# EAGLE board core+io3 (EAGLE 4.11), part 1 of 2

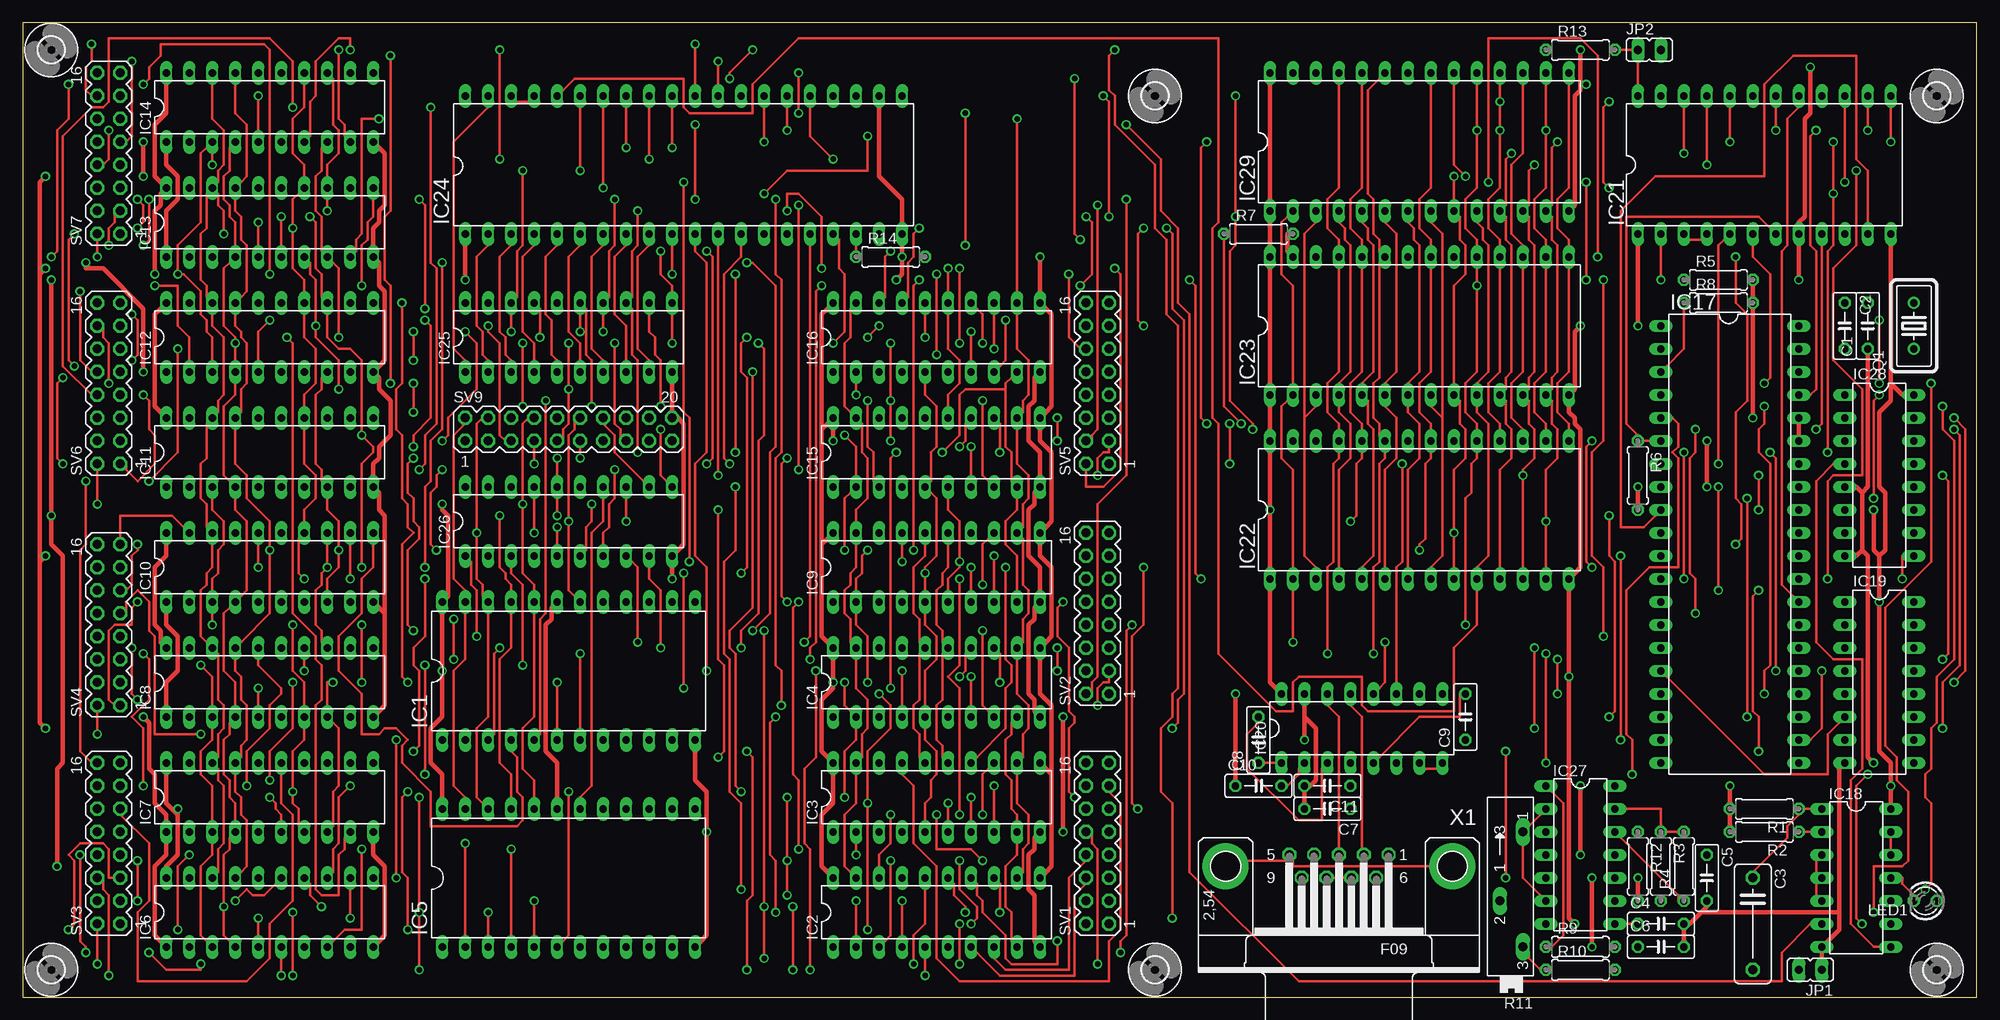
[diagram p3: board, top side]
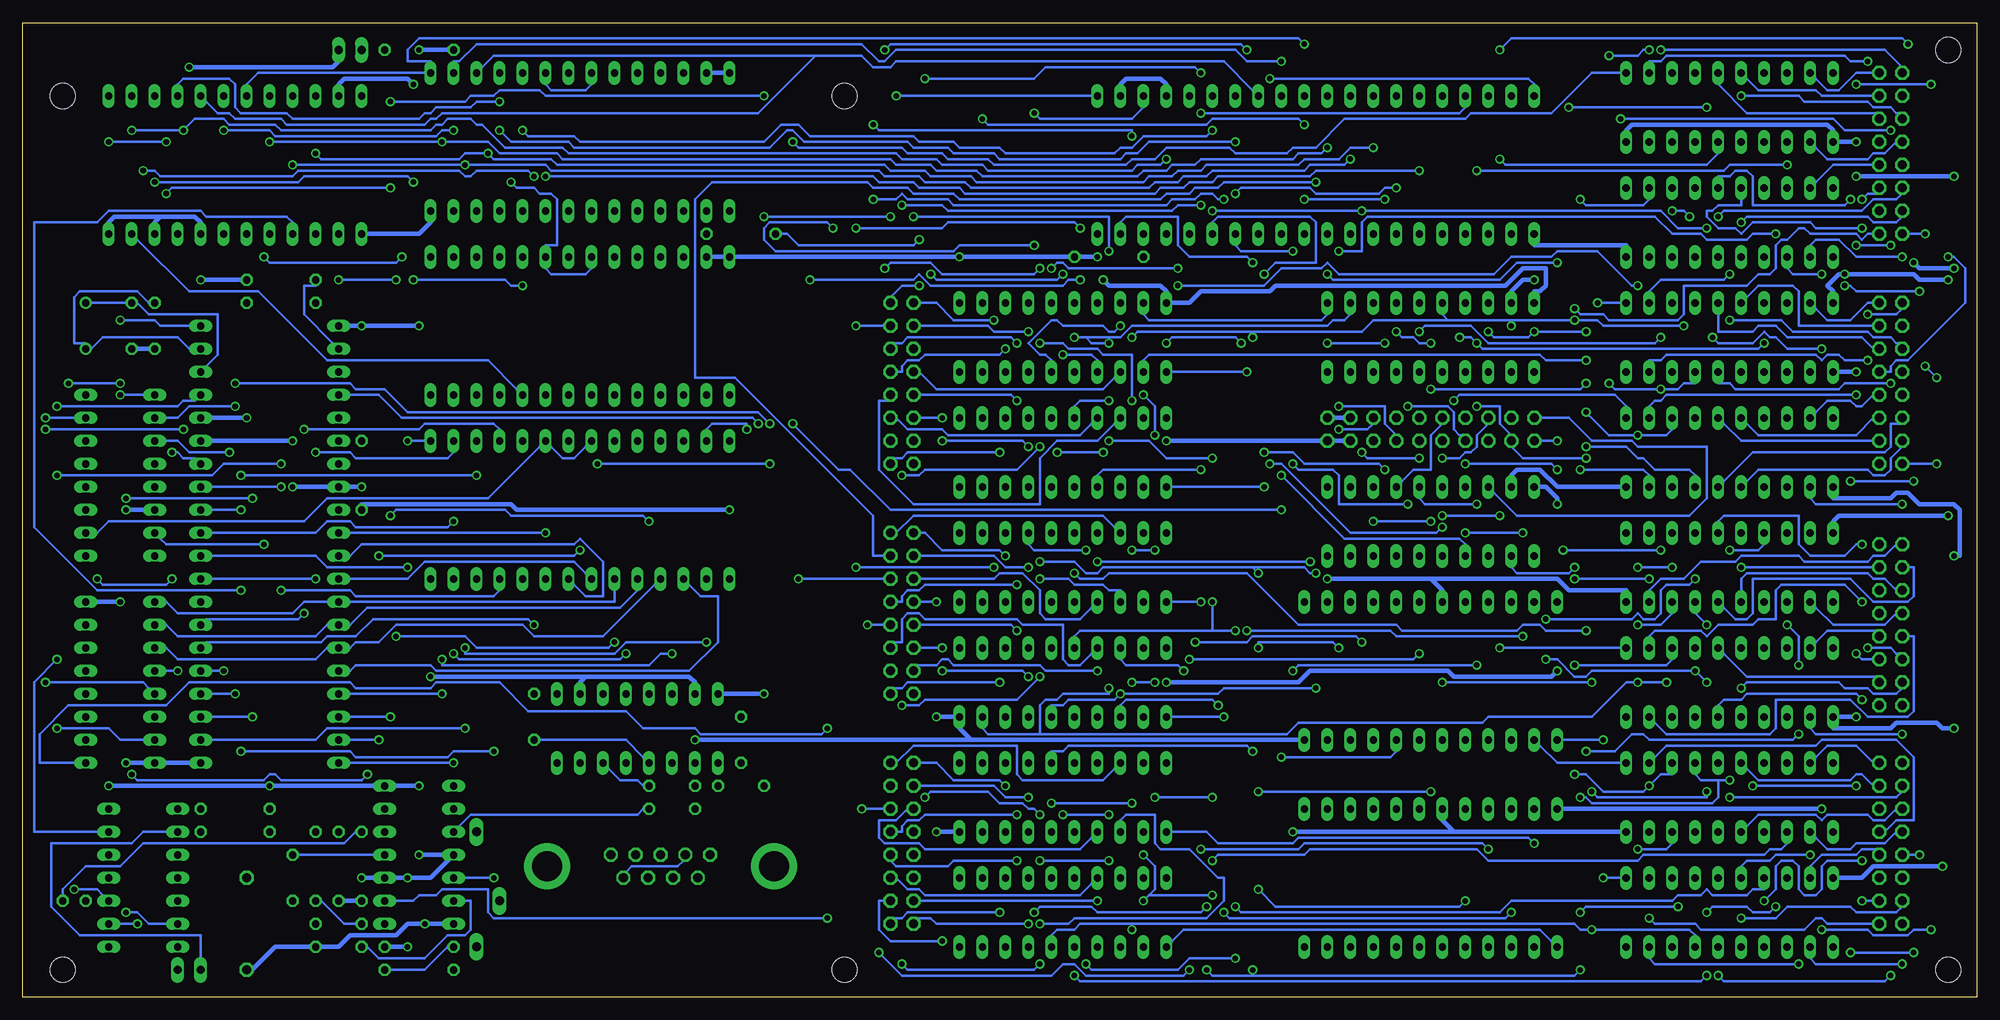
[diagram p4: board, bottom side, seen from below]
Size 215.88 x 107.62 mm. Coordinates in mm from the lower left corner, seen from the top.
Outline: 0,0 215.88,0 215.88,107.62 0,107.62 0,0
Copper layers (1*16): Top 0.035mm / dielectric 1.5mm / Bottom 0.035mm
Design rules "default": minimum track width 10mil, minimum drill 24mil, track to track 8mil, track to pad 8mil, pad to pad 8mil, via to via 8mil, smd to smd 8mil, copper to edge 40mil, drill to drill 8mil, minimum pad ring 10mil, minimum via ring 8mil, stop-mask expansion 4mil, vias tented up to drill 0mil, thermal gap 10mil
Net classes: 1 Power: width 0.508 mm, drill 0.254 mm, clearance 0.254 mm

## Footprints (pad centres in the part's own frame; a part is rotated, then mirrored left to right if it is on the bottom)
C050-025X075 = drill 0.813 octagon: 1 -2.54,0; 2 2.54,0
C102-043X133 = drill 1.016 octagon: 1 -5.08,0; 2 5.08,0
DIL24-6 = drill 0.813 long: 1 -13.97,-7.62; 2 -11.43,-7.62; 3 -8.89,-7.62; 4 -6.35,-7.62; 5 -3.81,-7.62; 6 -1.27,-7.62; 7 1.27,-7.62; 8 3.81,-7.62; 9 6.35,-7.62; 10 8.89,-7.62; 11 11.43,-7.62; 12 13.97,-7.62; 13 13.97,7.62; 14 11.43,7.62; 15 8.89,7.62; 16 6.35,7.62; 17 3.81,7.62; 18 1.27,7.62; 19 -1.27,7.62; 20 -3.81,7.62; 21 -6.35,7.62; 22 -8.89,7.62; 23 -11.43,7.62; 24 -13.97,7.62
DIL20 = drill 0.813 long: 1 -11.43,-3.81; 2 -8.89,-3.81; 3 -6.35,-3.81; 4 -3.81,-3.81; 5 -1.27,-3.81; 6 1.27,-3.81; 7 3.81,-3.81; 8 6.35,-3.81; 9 8.89,-3.81; 10 11.43,-3.81; 11 11.43,3.81; 12 8.89,3.81; 13 6.35,3.81; 14 3.81,3.81; 15 1.27,3.81; 16 -1.27,3.81; 17 -3.81,3.81; 18 -6.35,3.81; 19 -8.89,3.81; 20 -11.43,3.81
DIL40 = drill 0.813 long: 1 -24.13,-7.62; 2 -21.59,-7.62; 3 -19.05,-7.62; 4 -16.51,-7.62; 5 -13.97,-7.62; 6 -11.43,-7.62; 7 -8.89,-7.62; 8 -6.35,-7.62; 9 -3.81,-7.62; 10 -1.27,-7.62; 11 1.27,-7.62; 12 3.81,-7.62; 13 6.35,-7.62; 14 8.89,-7.62; 15 11.43,-7.62; 16 13.97,-7.62; 17 16.51,-7.62; 18 19.05,-7.62; 19 21.59,-7.62; 20 24.13,-7.62; 21 24.13,7.62; 22 21.59,7.62; 23 19.05,7.62; 24 16.51,7.62; 25 13.97,7.62; 26 11.43,7.62; 27 8.89,7.62; 28 6.35,7.62; 29 3.81,7.62; 30 1.27,7.62; 31 -1.27,7.62; 32 -3.81,7.62; 33 -6.35,7.62; 34 -8.89,7.62; 35 -11.43,7.62; 36 -13.97,7.62; 37 -16.51,7.62; 38 -19.05,7.62; 39 -21.59,7.62; 40 -24.13,7.62
DIL14 = drill 0.813 long: 1 -7.62,-3.81; 2 -5.08,-3.81; 3 -2.54,-3.81; 4 0,-3.81; 5 2.54,-3.81; 6 5.08,-3.81; 7 7.62,-3.81; 8 7.62,3.81; 9 5.08,3.81; 10 2.54,3.81; 11 0,3.81; 12 -2.54,3.81; 13 -5.08,3.81; 14 -7.62,3.81
DIL16 = drill 0.813 long: 1 -8.89,-3.81; 2 -6.35,-3.81; 3 -3.81,-3.81; 4 -1.27,-3.81; 5 1.27,-3.81; 6 3.81,-3.81; 7 6.35,-3.81; 8 8.89,-3.81; 9 8.89,3.81; 10 6.35,3.81; 11 3.81,3.81; 12 1.27,3.81; 13 -1.27,3.81; 14 -3.81,3.81; 15 -6.35,3.81; 16 -8.89,3.81
DIL24 = drill 0.813 long: 1 -13.97,-7.62; 2 -11.43,-7.62; 3 -8.89,-7.62; 4 -6.35,-7.62; 5 -3.81,-7.62; 6 -1.27,-7.62; 7 1.27,-7.62; 8 3.81,-7.62; 9 6.35,-7.62; 10 8.89,-7.62; 11 11.43,-7.62; 12 13.97,-7.62; 13 13.97,7.62; 14 11.43,7.62; 15 8.89,7.62; 16 6.35,7.62; 17 3.81,7.62; 18 1.27,7.62; 19 -1.27,7.62; 20 -3.81,7.62; 21 -6.35,7.62; 22 -8.89,7.62; 23 -11.43,7.62; 24 -13.97,7.62
DIL28 = drill 0.813 long: 1 -16.51,-7.62; 2 -13.97,-7.62; 3 -11.43,-7.62; 4 -8.89,-7.62; 5 -6.35,-7.62; 6 -3.81,-7.62; 7 -1.27,-7.62; 8 1.27,-7.62; 9 3.81,-7.62; 10 6.35,-7.62; 11 8.89,-7.62; 12 11.43,-7.62; 13 13.97,-7.62; 14 16.51,-7.62; 15 16.51,7.62; 16 13.97,7.62; 17 11.43,7.62; 18 8.89,7.62; 19 6.35,7.62; 20 3.81,7.62; 21 1.27,7.62; 22 -1.27,7.62; 23 -3.81,7.62; 24 -6.35,7.62; 25 -8.89,7.62; 26 -11.43,7.62; 27 -13.97,7.62; 28 -16.51,7.62
JP1 = drill 0.914 long: 1 0,-1.27; 2 0,1.27
LED3MM = drill 0.813 octagon: A -1.27,0; K 1.27,0
HC18U-V = drill 0.813 round: 1 -2.54,0; 2 2.54,0
0207/7 = drill 0.813 octagon: 1 -3.81,0; 2 3.81,0
SP19L = drill 1.016 long: A 5.715,-1.27; E -6.985,-1.27; S -1.905,1.27
MA08-2 = drill 1.016 octagon: 1 -8.89,-1.27; 2 -8.89,1.27; 3 -6.35,-1.27; 4 -6.35,1.27; 5 -3.81,-1.27; 6 -3.81,1.27; 7 -1.27,-1.27; 8 -1.27,1.27; 9 1.27,-1.27; 10 1.27,1.27; 11 3.81,-1.27; 12 3.81,1.27; 13 6.35,-1.27; 14 6.35,1.27; 15 8.89,-1.27; 16 8.89,1.27
MA10-2 = drill 1.016 octagon: 1 -11.43,-1.27; 2 -11.43,1.27; 3 -8.89,-1.27; 4 -8.89,1.27; 5 -6.35,-1.27; 6 -6.35,1.27; 7 -3.81,-1.27; 8 -3.81,1.27; 9 -1.27,-1.27; 10 -1.27,1.27; 11 1.27,-1.27; 12 1.27,1.27; 13 3.81,-1.27; 14 3.81,1.27; 15 6.35,-1.27; 16 6.35,1.27; 17 8.89,-1.27; 18 8.89,1.27; 19 11.43,-1.27; 20 11.43,1.27
2,8 = hole 2.8: 0,0
F09HP = drill 1.016 octagon: 1 -5.486,-1.27; 2 -2.743,-1.27; 3 0,-1.27; 4 2.743,-1.27; 5 5.486,-1.27; 6 -4.115,1.27; 7 -1.372,1.27; 8 1.372,1.27; 9 4.115,1.27 | drill 3.302 pad 5.08 round: G1 -12.522,0; G2 12.522,0

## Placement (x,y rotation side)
C1  27pf  [C050-025X075]  203.83,74.13 90 top
C2  27pf  [C050-025X075]  201.29,74.13 270 top
C3  22uf  [C102-043X133]  191.13,8.09 270 top
C4  0.1uf  [C050-025X075]  180.97,8.09 0 top
C5  10uf  [C050-025X075]  186.05,13.17 270 top
C6  330pf  [C050-025X075]  180.97,5.55 0 top
C7  10uf  [C050-025X075]  144.14,20.79 180 top
C8  0.1uf  [C050-025X075]  136.52,28.41 90 top
C9  0.1uf  [C050-025X075]  159.38,30.95 90 top
C10  0.1uf  [C050-025X075]  136.52,23.33 0 top
C11  0.1uf  [C050-025X075]  144.14,23.33 180 top
IC1  74154N  [DIL24-6]  60.32,36.03 0 top
IC2  74LS373N  [DIL20]  100.96,9.36 0 top
IC3  74LS373N  [DIL20]  100.96,22.06 0 top
IC4  74LS373N  [DIL20]  100.96,34.76 0 top
IC5  74154N  [DIL24-6]  60.32,13.17 0 top
IC6  74LS374N  [DIL20]  27.3,9.36 0 top
IC7  74LS374N  [DIL20]  27.3,22.06 0 top
IC8  74LS374N  [DIL20]  27.3,34.76 0 top
IC9  74LS373N  [DIL20]  100.96,47.46 0 top
IC10  74LS374N  [DIL20]  27.3,47.46 0 top
IC11  74LS374N  [DIL20]  27.3,60.16 0 top
IC12  74LS374N  [DIL20]  27.3,72.86 0 top
IC13  74LS374N  [DIL20]  27.3,85.56 0 top
IC14  74LS374N  [DIL20]  27.3,98.26 0 top
IC15  74LS373N  [DIL20]  100.96,60.16 0 top
IC16  74LS373N  [DIL20]  100.96,72.86 0 top
IC17  [DIL40]  188.59,50 270 top
IC18  74LS00N  [DIL14]  202.56,13.17 270 top
IC19  74LS138N  [DIL16]  205.1,34.76 270 top
IC20  MAX232  [DIL16]  147.95,29.68 0 top
IC21  [DIL24]  192.4,91.91 0 top
IC22  5565  [DIL28]  154.3,53.81 0 top
IC23  2764  [DIL28]  154.3,74.13 0 top
IC24  [DIL40]  73.02,91.91 0 top
IC25  74LS245N  [DIL20]  60.32,72.86 0 top
IC26  74LS245N  [DIL20]  60.32,52.54 0 top
IC27  LM556N  [DIL14]  172.08,15.71 270 top
IC28  74LS138N  [DIL16]  205.1,57.62 270 top
IC29  2764  [DIL28]  154.3,94.45 0 top
JP1  RESET  [JP1]  197.48,3.01 90 top
JP2  DEBUG  [JP1]  179.7,104.61 270 top
LED1  [LED3MM]  210.18,10.63 180 top
Q1  4Mhz  [HC18U-V]  208.91,74.13 90 top
R1  10K  [0207/7]  192.4,20.79 180 top
R2  10K  [0207/7]  192.4,18.25 180 top
R3  100K  [0207/7]  180.97,14.44 270 top
R4  100K  [0207/7]  183.51,14.44 90 top
R5  3.3K  [0207/7]  187.32,79.21 0 top
R6  3.3K  [0207/7]  178.43,57.62 270 top
R7  3.3K  [0207/7]  136.52,84.29 0 top
R8  3.3K  [0207/7]  187.32,76.67 0 top
R9  1.8K  [0207/7]  172.08,5.55 0 top
R10  10K  [0207/7]  172.08,3.01 0 top
R11  10K  [SP19L]  164.46,12.54 90 top
R12  270  [0207/7]  178.43,14.44 270 top
R13  1K  [0207/7]  172.08,104.61 0 top
R14  3.3K  [0207/7]  95.88,81.75 0 top
SV1  [MA08-2]  118.74,16.98 90 top
SV2  [MA08-2]  118.74,42.38 90 top
SV3  [MA08-2]  9.52,16.98 90 top
SV4  [MA08-2]  9.52,41.11 90 top
SV5  [MA08-2]  118.74,67.78 90 top
SV6  [MA08-2]  9.52,67.78 90 top
SV7  [MA08-2]  9.52,93.18 90 top
SV9  [MA10-2]  60.32,62.7 0 top
U$1  [2,8]  125.09,3.01 0 top
U$2  [2,8]  125.09,99.53 0 top
U$3  [2,8]  3.17,104.61 0 top
U$4  [2,8]  3.17,3.01 0 top
U$5  [2,8]  211.45,99.53 0 top
U$6  [2,8]  211.45,3.01 0 top
X1  [F09HP]  145.41,14.44 180 top

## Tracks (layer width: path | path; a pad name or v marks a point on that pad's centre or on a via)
A00
  Top 0.254: IC17.9 180.34,53.17 179.06,51.91 176.53,51.91 176.53,86.83 180.34,90.64 192.4,90.64 192.4,100.8 195.57,103.97 202.56,103.97 202.56,92.55 203.83,91.28 203.83,85.56 IC21.11 | IC29.10 160.65,85.56 161.28,84.92 161.28,83.66 161.92,83.02 161.92,69.05 160.65,67.78 IC23.10 160.65,65.24 160.65,64.61 161.92,63.34 161.92,48.73 160.65,47.46 IC22.10 160.65,44.92 160.65,41.11 158.11,38.57 158.11,31.58 148.59,31.58 147.95,32.22 147.95,35.39 140.97,35.39 140.33,34.76 140.33,31.58 138.42,31.58 132.07,37.94 132.07,63.34 131.44,63.97 131.44,84.92 132.07,85.56 132.07,105.88 85.72,105.88 80.64,100.8 80.64,97.62 73.66,97.62 73.02,98.26 73.02,101.44 60.96,101.44 59.69,100.16 IC24.36
  Bottom 0.254: IC21.11 203.19,83.66 197.48,77.94 189.86,77.94 182.24,70.32 164.46,70.32 161.28,67.14 IC23.10
A01  (via drill 0.61)
  Top 0.254: IC22.9 158.11,47.46 v158.11,51.27 158.11,58.25 159.38,59.52 159.38,62.7 158.75,63.34 158.75,65.88 IC23.9 158.11,67.78 158.11,78.58 159.38,79.84 159.38,83.02 158.75,83.66 158.75,86.19 IC29.9 158.11,88.1 v158.11,90.64 | v61.59,91.28 61.59,98.26 IC24.35
  Bottom 0.254: v61.59,91.28 73.02,91.28 73.66,90.64 83.81,90.64 84.45,90 86.99,90 87.62,89.37 90.16,89.37 90.8,88.73 111.75,88.73 112.39,89.37 116.83,89.37 117.47,90 121.28,90 121.91,90.64 v158.11,90.64 | v158.11,51.27 179.7,51.27 IC17.10
A02
  Top 0.254: 156.84,63.97 156.84,48.73 155.57,47.46 IC22.8 | 156.84,63.97 155.57,65.24 IC23.8 | 156.84,63.97 156.84,84.29 155.57,85.56 IC29.8
  Bottom 0.254: IC17.11 179.7,48.73 178.43,50 154.94,50 154.3,50.63 151.76,48.09 151.76,44.28 153.66,44.28 154.94,45.55 IC22.8
A03
  Top 0.254: IC22.7 153.03,47.46 153.03,58.25 154.3,59.52 154.3,63.34 153.03,64.61 153.03,65.24 IC23.7 153.03,67.78 154.3,69.05 154.3,83.02 153.66,83.66 153.66,84.92 153.03,85.56 IC29.7
  Bottom 0.254: IC17.12 179.7,46.19 173.35,46.19 171.44,48.09 154.94,48.09 153.66,46.82 IC22.7
A04
  Top 0.254: IC29.6 150.49,85.56 151.76,84.29 151.76,69.05 150.49,67.78 IC23.6 150.49,65.24 151.76,63.97 151.76,59.52 150.49,58.25 150.49,47.46 IC22.6
  Bottom 0.254: IC22.6 150.49,44.92 150.49,43.65 179.7,43.65 IC17.13 182.24,43.65 184.78,43.65 186.05,42.38 198.75,42.38 200.02,43.65 IC19.1
A05
  Top 0.254: IC22.5 147.95,47.46 149.22,48.73 149.22,62.7 148.59,63.34 148.59,65.88 IC23.5 147.95,67.78 149.22,69.05 149.22,83.02 148.59,83.66 148.59,84.92 147.95,85.56 IC29.5
  Bottom 0.254: IC19.2 200.02,41.11 198.75,39.84 183.51,39.84 182.24,41.11 IC17.14 179.7,41.11 177.79,43.02 149.85,43.02 147.95,44.92 IC22.5
A06
  Top 0.254: IC22.4 145.41,47.46 145.41,58.25 146.68,59.52 146.68,63.34 145.41,64.61 145.41,65.24 IC23.4 145.41,67.78 146.68,69.05 146.68,83.02 146.04,83.66 146.04,84.92 145.41,85.56 IC29.4
  Bottom 0.254: IC19.3 200.02,38.57 198.75,37.3 183.51,37.3 182.24,38.57 IC17.15 179.7,38.57 179.06,39.2 176.53,39.2 174.62,41.11 160.65,41.11 159.38,39.84 151.76,39.84 146.04,45.55 IC22.4
A07
  Top 0.254: IC17.16 181.6,35.39 192.4,24.6 199.38,24.6 199.38,29.04 200.66,30.31 IC19.6 | 141.6,63.97 141.6,48.73 142.87,47.46 IC22.3 | 141.6,63.97 142.87,65.24 IC23.3 | 141.6,63.97 141.6,84.29 142.87,85.56 IC29.3
  Bottom 0.254: IC17.16 179.7,36.03 179.06,36.66 170.81,36.66 170.17,36.03 142.23,36.03 139.06,39.2 139.06,44.28 140.97,44.28 142.23,45.55 IC22.3
A08  (via drill 0.61)
  Top 0.254: IC29.25 145.41,100.8 145.41,89.37 144.14,88.1 144.14,84.92 145.41,83.66 145.41,83.02 IC23.25 145.41,80.48 145.41,69.05 144.14,67.78 144.14,64.61 145.41,63.34 145.41,62.7 IC22.25 145.41,60.16 145.41,59.52 144.78,58.89 144.78,48.09 144.14,47.46 v144.14,37.94 | v169.54,37.3 v169.54,33.49
  Bottom 0.254: v169.54,33.49 179.7,33.49 IC17.17 | v169.54,37.3 169.54,36.66 146.68,36.66 145.41,37.94 v144.14,37.94
A09  (via drill 0.61)
  Top 0.254: IC29.24 147.95,100.8 147.95,89.37 146.68,88.1 146.68,84.92 147.95,83.66 147.95,83.02 IC23.24 147.95,80.48 147.95,69.05 146.68,67.78 146.68,64.61 147.95,63.34 147.95,62.7 IC22.24 147.95,60.16 147.95,59.52 147.31,58.89 147.31,53.17 v146.68,52.54 | v175.25,30.95 175.89,31.58 175.89,48.09 175.25,48.73 v175.25,53.17
  Bottom 0.254: v175.25,30.95 179.7,30.95 IC17.18 | v175.25,53.17 174.62,53.81 162.56,53.81 161.92,53.17 147.31,53.17 v146.68,52.54
A10  (via drill 0.61)
  Top 0.254: IC29.21 155.57,100.8 155.57,89.37 154.3,88.1 154.3,84.92 155.57,83.66 155.57,83.02 IC23.21 155.57,80.48 155.57,69.05 154.3,67.78 154.3,64.61 155.57,63.34 155.57,62.7 IC22.21 155.57,60.16 155.57,59.52 154.94,58.89 154.94,50.63 154.3,50 v154.3,49.37 | v176.53,48.73 v176.53,28.41
  Bottom 0.254: v176.53,28.41 179.7,28.41 IC17.19 | v176.53,48.73 154.94,48.73 v154.3,49.37
A11  (via drill 0.61)
  Top 0.254: IC29.23 149.85,101.44 148.59,100.16 148.59,88.73 149.22,88.1 149.22,84.29 149.85,83.66 149.85,82.39 IC23.23 149.85,81.11 149.85,68.41 149.22,67.78 149.22,63.97 149.85,63.34 149.85,62.06 IC22.23 150.49,60.16 150.49,59.52 149.85,58.89 149.85,48.09 149.22,47.46 v149.22,37.94 | v168.27,37.94 v168.27,25.87
  Bottom 0.254: v168.27,25.87 179.7,25.87 IC17.20 | v168.27,37.94 167.63,37.3 149.85,37.3 v149.22,37.94
A12  (via drill 0.61)
  Top 0.254: v198.75,36.03 198.75,29.68 197.48,28.41 IC17.22 | IC29.2 139.69,86.19 139.06,85.56 139.06,79.84 140.33,78.58 140.33,67.78 IC23.2 139.69,65.88 139.06,65.24 139.06,59.52 140.33,58.25 140.33,47.46 IC22.2 140.33,44.92 v140.33,39.2 | v167,38.57 v167,29.68
  Bottom 0.254: v198.75,36.03 200.02,36.03 IC19.4 | v167,29.68 182.24,29.68 183.51,28.41 194.94,28.41 IC17.22 | v167,38.57 167,37.94 150.49,37.94 149.22,39.2 v140.33,39.2
A13  (via drill 0.61)
  Top 0.254: v190.5,55.08 v190.5,30.95 | v204.47,55.08 204.47,65.88 v205.1,66.51
  Bottom 0.254: v190.5,30.95 194.94,30.95 IC17.23 | v204.47,55.08 v190.5,55.08 | v205.1,66.51 202.56,66.51 IC28.1
A14  (via drill 0.61)
  Top 0.254: v192.4,33.49 192.4,36.03 193.03,36.66 193.03,58.89 191.76,60.16 191.76,62.7 192.4,63.34 v192.4,65.24
  Bottom 0.254: v192.4,33.49 194.94,33.49 IC17.24 | v192.4,65.24 197.48,65.24 198.75,63.97 200.02,63.97 IC28.2
A15  (via drill 0.61)
  Top 0.254: v193.67,36.03 193.67,59.52 v193.03,60.16
  Bottom 0.254: v193.67,36.03 194.94,36.03 IC17.25 | v193.03,60.16 197.48,60.16 198.75,61.43 200.02,61.43 IC28.3
AB\
  Bottom 0.254: IC22.22 153.66,60.8 154.94,59.52 156.2,59.52 157.47,60.8 IC22.20 158.75,60.8 164.46,55.08 182.24,55.08 184.78,52.54 206.37,52.54 207.64,51.27 IC28.10
CB1
  Top 0.254: R14.1 92.07,82.39 92.07,83.02 IC24.18
CD\  (via drill 0.61)
  Top 0.254: v207.64,46.19 207.64,48.73 IC28.9 | v199.38,46.19 199.38,56.98 200.02,57.62 203.19,57.62 203.19,67.14 200.02,70.32 200.02,80.48 202.56,83.02 v202.56,91.28 | v159.38,90.64 158.11,91.91 158.11,100.8 IC29.20
  Bottom 0.254: IC29.20 158.11,100.8 157.47,100.16 153.66,100.16 153.03,100.8 IC29.22 | v207.64,46.19 207,45.55 200.02,45.55 v199.38,46.19 | v202.56,91.28 201.29,91.28 200.66,90.64 186.05,90.64 185.41,91.28 167.63,91.28 167,90.64 166.37,90.64 165.73,91.28 160.01,91.28 v159.38,90.64
D0  (via drill 0.61)
  Top 0.254: IC22.11 163.19,47.46 163.19,58.25 164.46,59.52 164.46,62.7 163.82,63.34 163.82,65.88 IC23.11 163.82,67.14 163.82,68.41 164.46,69.05 164.46,83.02 163.82,83.66 163.82,86.19 IC29.11 163.82,87.47 163.82,92.55 v164.46,93.18 | v66.67,93.81 66.67,98.26 IC24.33 | v183.51,93.18 183.51,98.26 IC21.22 | v187.32,44.92 v187.32,56.35
  Bottom 0.254: v66.67,93.81 69.21,93.81 70.48,92.55 74.29,92.55 74.92,91.91 85.08,91.91 85.72,91.28 88.26,91.28 88.89,90.64 91.44,90.64 92.07,90 110.48,90 111.12,90.64 115.56,90.64 116.2,91.28 120.01,91.28 120.64,91.91 156.84,91.91 157.47,92.55 163.82,92.55 v164.46,93.18 167,93.18 167.63,92.55 182.88,92.55 v183.51,93.18 | v187.32,56.35 194.94,56.35 IC17.33 | v187.32,44.92 179.7,44.92 179.06,44.28 163.82,44.28 163.19,44.92 IC22.11
D1  (via drill 0.61)
  Top 0.254: IC22.12 165.73,47.46 v165.73,57.62 165.73,58.25 167,59.52 167,62.7 166.37,63.34 166.37,65.88 IC23.12 166.37,67.14 166.37,68.41 167,69.05 167,83.02 166.37,83.66 166.37,86.19 IC29.12 166.37,87.47 166.37,91.28 v167,91.91 | v69.21,92.55 69.21,98.26 IC24.32 | v186.05,91.91 186.05,98.26 IC21.21 | v191.76,57.62 v191.76,53.81
  Bottom 0.254: v69.21,92.55 69.84,91.91 73.66,91.91 74.29,91.28 84.45,91.28 85.08,90.64 87.62,90.64 88.26,90 90.8,90 91.44,89.37 111.12,89.37 111.75,90 116.2,90 116.83,90.64 120.64,90.64 121.28,91.28 157.47,91.28 158.11,91.91 v167,91.91 v186.05,91.91 | v191.76,53.81 194.94,53.81 IC17.32 | v165.73,57.62 v191.76,57.62
D2  (via drill 0.61)
  Top 0.254: IC22.13 168.27,47.46 v168.27,52.54 168.27,58.25 169.54,59.52 169.54,62.7 168.91,63.34 168.91,65.88 IC23.13 168.91,67.14 168.91,68.41 169.54,69.05 169.54,83.02 168.91,83.66 168.91,86.19 IC29.13 168.91,87.47 168.91,93.81 v169.54,94.45 | v71.75,93.81 71.75,98.26 IC24.31 | v188.59,94.45 188.59,98.26 IC21.20
  Bottom 0.254: v71.75,93.81 72.38,93.18 74.92,93.18 75.56,92.55 85.72,92.55 86.35,91.91 88.89,91.91 89.53,91.28 92.07,91.28 92.7,90.64 109.85,90.64 110.48,91.28 114.93,91.28 115.56,91.91 119.38,91.91 120.01,92.55 156.2,92.55 156.84,93.18 163.19,93.18 164.46,94.45 v169.54,94.45 v188.59,94.45 | v168.27,52.54 168.91,51.91 179.06,51.91 179.7,52.54 182.24,52.54 183.51,51.27 194.94,51.27 IC17.31
D3  (via drill 0.61)
  Top 0.254: IC22.15 170.81,62.7 170.81,63.34 169.54,64.61 169.54,67.78 170.81,69.05 170.81,80.48 IC23.15 170.81,83.02 170.81,83.66 169.54,84.92 169.54,88.1 170.81,89.37 170.81,100.8 IC29.15 | v74.29,105.25 74.29,100.8 IC24.30 | v173.35,47.46 172.72,48.09 172.72,60.8 v173.35,61.43
  Bottom 0.254: v74.29,105.25 74.92,105.88 172.08,105.88 173.35,104.61 173.35,103.34 170.81,103.34 IC29.15 171.44,102.07 189.86,102.07 191.13,100.8 IC21.19 | v173.35,47.46 182.24,47.46 183.51,48.73 194.94,48.73 IC17.30 | v173.35,61.43 171.44,61.43 IC22.15
D4  (via drill 0.61)
  Top 0.254: IC22.16 168.27,62.7 168.27,63.34 167,64.61 167,67.78 168.27,69.05 168.27,80.48 IC23.16 168.27,83.02 168.27,83.66 167,84.92 167,88.1 168.27,89.37 v168.27,95.72 168.27,100.8 IC29.16 | v76.83,103.34 76.83,100.8 IC24.29 | v193.67,95.72 193.67,98.26 IC21.18 | v183.51,60.16 v183.51,46.19
  Bottom 0.254: v76.83,103.34 80.64,103.34 81.91,104.61 119.38,104.61 120.64,103.34 121.28,103.34 123.19,105.25 165.73,105.25 167.63,103.34 168.27,103.34 IC29.16 | v193.67,95.72 188.59,95.72 187.95,95.08 170.17,95.08 169.54,95.72 v168.27,95.72 | v183.51,46.19 194.94,46.19 IC17.29 | v183.51,60.16 179.7,60.16 179.06,59.52 168.91,59.52 168.27,60.16 IC22.16
D5
  Top 0.254: IC17.28 195.57,44.28 194.31,45.55 194.31,82.39 194.94,83.02 194.94,96.99 196.21,98.26 IC21.17 | IC22.17 165.73,62.7 164.46,63.97 164.46,67.78 165.73,69.05 165.73,80.48 IC23.17 165.73,83.02 164.46,84.29 164.46,91.91 165.73,93.18 165.73,100.8 IC29.17
  Bottom 0.254: 128.27,103.97 163.82,103.97 165.09,102.7 IC29.17 | 128.27,103.97 123.19,103.97 121.91,102.7 120.01,102.7 119.38,103.34 83.18,103.34 80,100.16 IC24.28 | 128.27,103.97 134.62,97.62 169.54,97.62 170.17,96.99 170.81,96.99 171.44,96.36 186.69,96.36 187.32,96.99 192.4,96.99 193.03,97.62 194.31,97.62 195.57,98.89 IC21.17
D6  (via drill 0.61)
  Top 0.254: IC22.18 163.19,62.7 163.19,63.34 161.92,64.61 161.92,67.78 163.19,69.05 163.19,80.48 IC23.18 163.19,83.02 163.19,83.66 161.92,84.92 161.92,88.1 163.19,89.37 v163.19,95.72 v163.19,98.89 163.19,100.8 IC29.18 | v81.91,94.45 81.91,98.26 IC24.27 | v184.78,42.38 184.78,46.19 184.14,46.82 184.14,59.52 184.78,60.16 v184.78,62.7
  Bottom 0.254: v81.91,94.45 91.44,94.45 92.7,93.18 93.97,93.18 94.61,92.55 107.94,92.55 108.58,93.18 113.02,93.18 113.66,93.81 117.47,93.81 118.1,94.45 129.53,94.45 130.81,95.72 131.44,95.72 133.34,93.81 154.94,93.81 155.57,94.45 161.92,94.45 v163.19,95.72 | v184.78,42.38 185.41,41.74 195.57,41.74 IC17.27 | v184.78,62.7 172.08,62.7 171.44,63.34 163.82,63.34 163.19,62.7 IC22.18 | v163.19,98.89 165.73,98.89 166.37,98.26 170.17,98.26 170.81,97.62 171.44,97.62 172.08,96.99 186.05,96.99 186.69,97.62 191.76,97.62 192.4,98.26 192.4,100.8 193.03,101.44 198.12,101.44 198.75,100.8 IC21.16
D7  (via drill 0.61)
  Top 0.254: IC29.19 160.65,100.8 v160.65,95.72 160.65,89.37 159.38,88.1 159.38,84.92 160.65,83.66 160.65,83.02 IC23.19 160.65,80.48 v160.65,78.58 160.65,69.05 159.38,67.78 159.38,64.61 160.65,63.34 160.65,62.7 IC22.19 160.65,60.16 160.65,59.52 160.01,58.89 160.01,55.71 159.38,55.08 v159.38,41.11 | v84.45,95.72 84.45,98.26 IC24.26 | v201.29,90 201.29,98.26 IC21.15 | v172.72,79.21 v172.72,90
  Bottom 0.254: v84.45,95.72 85.08,95.08 92.07,95.08 93.34,93.81 94.61,93.81 95.24,93.18 107.31,93.18 107.94,93.81 112.39,93.81 113.02,94.45 116.83,94.45 117.47,95.08 128.9,95.08 130.17,96.36 132.07,96.36 133.98,94.45 154.3,94.45 154.94,95.08 160.01,95.08 v160.65,95.72 | v159.38,41.11 160.01,41.74 177.16,41.74 179.06,39.84 182.24,39.84 182.88,39.2 195.57,39.2 IC17.26 | v201.29,90 185.41,90 184.78,90.64 173.35,90.64 v172.72,90 | v172.72,79.21 162.56,79.21 161.92,78.58 v160.65,78.58
E  (via drill 0.61)
  Top 0.254: v198.12,95.72 197.48,95.08 197.48,83.02 198.12,82.39 198.12,67.14 197.48,66.51 IC17.37 | v203.83,95.72 203.83,98.26 IC21.14 | v89.53,92.55 86.99,95.08 86.99,98.26 IC24.25 | v210.18,11.9 210.81,12.54 210.81,21.42 210.18,22.06 210.18,24.6 210.81,25.23 210.81,29.68 211.45,30.31 211.45,35.39 213.35,37.3 213.35,61.43 212.09,62.7 v212.09,65.24
  Bottom 0.254: v203.83,95.72 v198.12,95.72 196.84,96.99 193.67,96.99 193.03,96.36 187.95,96.36 187.32,95.72 170.81,95.72 170.17,96.36 169.54,96.36 168.91,96.99 166.37,96.99 165.73,96.36 165.09,96.36 162.56,93.81 156.2,93.81 155.57,93.18 119.38,93.18 118.74,92.55 114.93,92.55 114.3,91.91 109.85,91.91 109.21,91.28 93.34,91.28 92.7,91.91 90.16,91.91 v89.53,92.55 | v210.18,11.9 207.64,11.9 207,11.27 IC18.10 | v212.09,65.24 198.75,65.24 198.12,65.88 196.84,65.88 IC17.37
EF\  (via drill 0.61)
  Top 0.254: v189.22,50 189.86,50.63 189.86,54.45 189.22,55.08 189.22,64.61 190.5,65.88 190.5,75.4 189.22,76.67 v189.22,81.75 | v173.98,81.75 173.98,103.97 172.08,105.88 161.92,105.88 v161.92,90
  Bottom 0.254: IC23.22 153.03,80.48 153.66,79.84 157.47,79.84 158.11,80.48 IC23.20 158.11,83.02 156.84,83.02 156.84,88.1 157.47,88.73 158.75,88.73 159.38,89.37 161.28,89.37 v161.92,90 | v189.22,50 200.02,50 200.66,50.63 IC28.7 | v189.22,81.75 188.59,81.11 174.62,81.11 v173.98,81.75
GND  (via drill 0.61)
  Top 0.508: 203.19,49.37 202.56,48.73 IC28.8 | 203.19,49.37 203.19,55.71 | 203.19,55.71 203.83,56.35 203.83,70.95 C1.1 | 203.19,55.71 202.56,56.35 IC28.5 | C6.2 183.51,6.18 183.51,7.46 C4.2 184.14,8.09 185.41,9.36 | 203.19,49.37 203.83,48.73 203.83,26.5 v204.47,25.87 | C7.2 141.6,21.42 141.6,22.7 C11.2 142.23,23.33 142.87,23.96 142.87,29.68 141.6,30.95 | 141.6,30.95 141.6,32.22 IC20.15 | v178.43,74.13 178.43,83.02 IC21.1 | 172.08,100.8 172.08,100.16 171.44,99.53 171.44,87.47 IC29.14 | 172.08,100.8 v172.08,104.61 | 172.08,100.8 v172.72,100.8 | v172.08,74.13 171.44,73.5 171.44,67.14 IC23.14 170.81,65.24 170.81,64.61 171.44,63.97 171.44,63.34 172.08,62.7 172.08,47.46 171.44,46.82 IC22.14 170.81,44.92 v170.81,35.39 170.81,8.73 v171.44,8.09 | IC13.1 15.87,83.02 15.87,86.83 17.14,88.1 17.14,90.64 15.87,91.91 15.87,93.18 IC14.1 | IC6.1 15.24,6.18 14.6,6.82 14.6,14.44 15.87,15.71 15.87,16.98 IC7.1 15.87,19.52 15.87,20.15 14.6,21.42 14.6,24.6 13.97,25.23 13.97,30.31 v13.33,30.95 | IC10.1 15.87,42.38 15.87,41.11 17.14,39.84 17.14,36.03 15.87,34.76 15.87,32.22 IC8.1 | 1.9,48.09 v2.54,48.73 | 1.9,48.09 1.9,30.31 v2.54,29.68 | v13.33,69.05 13.33,76.03 8.89,80.48 6.98,80.48 v6.98,81.11 | 1.9,79.84 v2.54,80.48 | 1.9,79.84 1.9,48.09 | v13.33,94.45 v13.33,90.64 | v2.54,90.64 1.9,90 1.9,79.84 | v48.89,79.21 48.89,83.02 IC24.1 | IC14.10 39.37,93.81 40,93.18 40,87.47 39.37,86.83 39.37,85.56 38.73,84.92 38.73,83.02 IC13.10 39.37,81.11 39.37,78.58 40,77.94 40,70.32 39.37,69.69 IC12.10 39.37,68.41 39.37,67.14 40.64,65.88 40.64,62.06 39.37,60.8 39.37,59.52 38.73,58.89 38.73,57.62 IC11.10 39.37,55.71 39.37,53.81 40,53.17 40,42.38
  Top 0.508: 40,42.38 40,32.22 39.37,31.58 IC8.10 | 40,42.38 39.37,43.02 IC10.10 | IC16.10 111.75,68.41 111.75,65.88 111.12,65.24 111.12,61.43 112.39,60.16 112.39,57.62 IC15.10 111.75,55.71 111.75,54.45 111.12,53.81 111.12,48.73 112.39,47.46 112.39,44.92 IC9.10 111.75,43.02 111.75,41.74 111.12,41.11 111.12,33.49 111.75,32.85 111.75,31.58 IC4.10 | IC2.10 111.75,6.18 111.75,11.27 111.12,11.9 111.12,15.71 111.75,16.34 111.75,17.61 IC3.10 | v114.93,30.95 v114.93,18.25 | IC25.10 71.75,67.78 71.75,64.61 SV9.20 72.38,63.97 73.02,63.34 73.02,50 72.38,49.37 IC26.10 71.75,47.46 v71.75,46.19 | IC5.12 74.92,6.18 75.56,6.82 v75.56,18.25 75.56,22.7 74.29,23.96 74.29,27.14 IC1.12 | IC6.10 39.37,6.18 40,6.82 40,14.44 38.73,15.71 38.73,16.98 IC7.10 | IC1.19 58.41,43.02 58.41,41.74 57.78,41.11 57.78,27.14 59.05,25.87 59.05,22.06 IC5.19 | 141.6,30.95 v141.6,28.41 | 200.66,9.36 200.66,25.23 IC19.8 | 200.66,9.36 200.66,7.46 199.38,6.18 IC18.7 198.75,4.92 198.75,4.28 JP1.1 | 185.41,9.36 186.05,10 C5.2 | 185.41,9.36 200.66,9.36
  Bottom 0.508: C2.2 201.92,71.59 203.19,71.59 C1.1 | IC27.7 169.54,8.09 v171.44,8.09 173.35,8.09 174.62,6.82 179.7,6.82 180.97,5.55 182.88,5.55 C6.2 184.14,5.55 187.95,5.55 190.5,3.01 C3.2 | IC17.21 197.48,25.87 200.02,25.87 IC19.8 202.56,25.87 v204.47,25.87 | 153.66,35.39 142.23,35.39 141.6,34.76 IC20.15 | 153.66,35.39 154.3,34.76 IC20.10 | IC29.14 170.81,85.56 172.08,84.29 177.79,84.29 IC21.1 | IC17.1 179.7,74.13 v178.43,74.13 v172.08,74.13 | v172.08,104.61 168.91,104.61 R13.1 | v172.72,100.8 173.35,101.44 180.34,101.44 180.97,100.8 IC21.23 | v170.81,35.39 153.66,35.39 | v13.33,30.95 15.24,30.95 IC8.1 15.87,29.68 9.52,29.68 8.89,30.31 4.44,30.31 3.8,29.68 v2.54,29.68 | v2.54,48.73 1.9,48.73 1.9,53.81 2.54,54.45 6.34,54.45 7.62,55.71 8.89,55.71 9.52,55.08 15.87,55.08 IC11.1 | v13.33,69.05 15.24,69.05 IC12.1 | v6.98,81.11 6.34,80.48 v2.54,80.48 | v13.33,94.45 15.24,94.45 IC14.1 15.87,95.72 16.5,96.36 38.1,96.36 38.73,95.72 IC14.10 | v13.33,90.64 v2.54,90.64 | IC24.1 48.89,83.02 38.73,83.02 IC13.10 | v48.89,79.21 50.16,79.21 51.43,77.94 IC25.19 | IC26.19 51.43,57.62 50.8,58.25 48.26,58.25 46.35,56.35 39.37,56.35 IC11.10 | v114.93,30.95 113.02,30.95 IC4.10 112.39,29.68 111.12,28.41 | v114.93,18.25 113.02,18.25 IC3.10 | SV9.18 69.84,63.97 71.11,63.97 SV9.20 | 60.32,46.19 59.05,44.92 IC1.19 | 60.32,46.19 v71.75,46.19 | 57.78,18.25 59.05,19.52 IC5.19 | 57.78,18.25 39.37,18.25 IC7.10 | v75.56,18.25 57.78,18.25 | 111.12,28.41 74.92,28.41 IC1.12 | 60.32,46.19 46.35,46.19 45.08,44.92 38.73,44.92 IC10.10 | v141.6,28.41 111.12,28.41
HLT\
  Bottom 0.254: IC17.2 181.6,72.22 184.78,75.4 184.78,78.58 183.51,78.58 R5.1
IN00
  Bottom 0.254: IC5.1 46.98,6.18 48.26,7.46 87.62,7.46 88.89,6.18 IC2.1
IN01  (via drill 0.61)
  Top 0.254: v48.89,16.98 48.89,6.82 IC5.2
  Bottom 0.254: v48.89,16.98 49.53,17.61 74.92,17.61 75.56,16.98 83.81,16.98 85.08,18.25 88.89,18.25 IC3.1
IN02  (via drill 0.61)
  Top 0.254: v51.43,9.36 51.43,6.82 IC5.3 | v83.18,9.36 83.18,15.08 82.55,15.71 82.55,30.31 v83.18,30.95
  Bottom 0.254: v51.43,9.36 52.07,8.73 82.55,8.73 v83.18,9.36 | v83.18,30.95 88.89,30.95 IC4.1
IN03  (via drill 0.61)
  Top 0.254: v53.97,16.34 53.97,6.82 IC5.4 | v85.72,16.34 85.72,23.96 85.08,24.6 85.08,43.02 v85.72,43.65
  Bottom 0.254: v53.97,16.34 54.61,16.98 74.29,16.98 74.92,16.34 v85.72,16.34 | v85.72,43.65 88.89,43.65 IC9.1
IN04  (via drill 0.61)
  Top 0.254: v56.51,10.63 56.51,6.82 IC5.5 | v79.37,11.9 79.37,21.42 78.1,22.7 78.1,37.3 77.46,37.94 77.46,48.09 78.73,49.37 v78.73,56.35
  Bottom 0.254: v56.51,10.63 57.15,10 77.46,10 v79.37,11.9 | v78.73,56.35 88.89,56.35 IC15.1
IN05  (via drill 0.61)
  Top 0.254: v60.32,22.7 60.32,6.82 59.69,6.18 IC5.6 | v79.37,22.7 78.73,23.33 78.73,37.94 78.1,38.57 78.1,40.48 80.64,43.02 v80.64,69.05
  Bottom 0.254: v60.32,22.7 v79.37,22.7 | v80.64,69.05 88.89,69.05 IC16.1
IO-E\  (via drill 0.61)
  Top 0.254: v104.13,83.02 v104.13,97.62 | v126.36,84.92 126.99,84.29 126.99,76.03 128.27,74.77 128.27,33.49 127.63,32.85 127.63,30.31 v126.99,29.68
  Bottom 0.254: v104.13,97.62 103.5,96.99 93.34,96.99 92.07,98.26 IC24.23 | v104.13,83.02 112.39,83.02 113.02,82.39 132.71,82.39 133.98,83.66 133.98,84.92 133.34,85.56 126.99,85.56 v126.36,84.92 | v126.99,29.68 127.63,29.04 140.97,29.04 141.6,29.68 147.31,29.68 149.22,31.58 160.01,31.58 163.19,34.76 170.17,34.76 170.81,34.12 179.06,34.12 179.7,34.76 197.48,34.76 200.02,32.22 210.81,32.22 213.99,29.04 213.99,25.87 210.18,25.87 IC19.9
IO-F\  (via drill 0.61)
  Top 0.254: v198.12,62.7 198.75,63.34 198.75,83.02 IC21.9 | v213.35,62.7 213.99,62.06 213.99,36.66 212.09,34.76 v212.09,29.68
  Bottom 0.254: v198.12,62.7 v213.35,62.7 | v212.09,29.68 206.37,29.68 205.1,28.41 202.56,28.41 IC19.7
IRQ\  (via drill 0.61)
  Top 0.254: IC24.37 55.88,98.89 54.61,98.89 IC24.38 | v134.62,63.34 132.71,65.24 132.71,83.66 R7.1 | v85.72,97.62 v85.72,102.07 | v116.2,101.44 116.2,84.29 v116.83,83.66
  Bottom 0.254: v134.62,63.34 135.25,63.97 173.98,63.97 176.53,66.51 179.7,66.51 IC17.4 | v85.72,97.62 57.15,97.62 56.51,98.26 IC24.37 | v85.72,102.07 86.35,102.7 102.86,102.7 104.13,101.44 v116.2,101.44 | v116.83,83.66 117.47,83.02 130.17,83.02 131.44,84.29 132.07,84.29 R7.1
MR
  Top 0.254: IC17.3 181.6,69.69 183.51,71.59 183.51,76.03 R8.1
N$1  (via drill 0.61)
  Top 0.254: v118.74,3.64 118.74,16.34 118.1,16.98 118.1,18.25 SV1.10 | v103.5,8.09 v103.5,3.64
  Bottom 0.254: v118.74,3.64 118.1,3.01 104.13,3.01 v103.5,3.64 | v103.5,8.09 100.32,8.09 99.69,8.73 85.08,8.73 83.18,10.63 83.18,13.17 83.81,13.17 86.99,16.34 90.16,16.34 90.8,16.98 90.8,20.15 93.97,20.15 94.61,19.52 IC3.3
N$2
  Bottom 0.254: IC3.4 97.78,17.61 99.05,16.34 116.2,16.34 116.83,16.98 120.64,16.98 121.28,17.61 121.28,19.52 119.38,19.52 118.1,20.79 SV1.12
N$3
  Bottom 0.254: IC17.39 197.48,71.59 198.75,72.86 207,72.86 208.28,71.59 Q1.1 208.91,72.22 210.18,72.22 210.18,77.3 209.54,77.94 203.19,77.94 201.92,76.67 C2.1
N$4
  Bottom 0.254: IC17.38 195.57,69.69 194.31,70.95 194.31,75.4 201.92,75.4 203.19,76.67 C1.2 204.47,76.67 208.28,76.67 Q1.2
N$5
  Top 0.254: IC25.2 51.43,70.32 50.8,70.95 50.8,73.5 50.16,74.13 50.16,81.75 51.43,83.02 IC24.2
N$6
  Top 0.254: IC18.5 198.12,11.27 198.12,12.54 IC18.4 198.12,13.81 198.12,15.08 IC18.3
N$7  (via drill 0.61)
  Top 0.254: v104.77,22.06 104.77,19.52 IC3.7
  Bottom 0.254: v104.77,22.06 107.31,22.06 108.58,23.33 116.83,23.33 SV1.14
N$8  (via drill 0.61)
  Top 0.254: v107.31,23.33 107.31,19.52 IC3.8
  Bottom 0.254: v107.31,23.33 107.94,23.96 113.02,23.96 114.93,25.87 116.83,25.87 SV1.16
N$9
  Top 0.254: IC2.8 107.31,4.28 108.58,3.01 115.56,3.01 115.56,13.17 117.47,15.08 SV1.8
N$10
  Top 0.254: IC2.7 105.41,4.92 107.94,2.38 116.2,2.38 116.2,11.27 117.47,12.54 SV1.6
N$11  (via drill 0.61)
  Top 0.254: v97.15,10.63 97.15,6.82 IC2.4
  Bottom 0.254: v97.15,10.63 116.83,10.63 SV1.4
N$12  (via drill 0.61)
  Top 0.254: v95.88,15.08 95.88,6.82 95.24,6.18 IC2.3 | v103.5,15.08 103.5,11.9 105.41,10 105.41,8.73 v104.77,8.09
  Bottom 0.254: v95.88,15.08 v103.5,15.08 | v104.77,8.09 114.93,8.09 115.56,8.73 117.47,8.73 SV1.2
N$13  (via drill 0.61)
  Top 0.254: v107.94,9.36 107.94,12.54 IC2.13
  Bottom 0.254: v107.94,9.36 118.1,9.36 118.74,8.73 120.01,8.73 SV1.1
N$14  (via drill 0.61)
  Top 0.254: v114.3,6.18 114.3,3.64 109.21,3.64 108.58,4.28 108.58,6.82 106.04,9.36 106.04,10.63 105.41,11.27 105.41,12.54 IC2.14
  Bottom 0.254: v114.3,6.18 120.01,6.18 121.28,7.46 121.28,10.63 120.64,10.63 SV1.3
N$15
  Bottom 0.254: IC2.17 97.78,12.54 99.05,11.27 116.2,11.27 116.83,11.9 118.1,11.9 119.38,13.17 SV1.5
N$16  (via drill 0.61)
  Top 0.254: v106.04,15.08 104.77,16.34 100.96,16.34 v100.96,20.15 | v95.88,20.15 95.88,16.98 94.61,15.71 94.61,14.44 IC2.18
  Bottom 0.254: v106.04,15.08 113.02,15.08 113.66,14.44 119.38,14.44 120.01,15.08 SV1.7 | v95.88,20.15 v100.96,20.15
N$17  (via drill 0.61)
  Top 0.254: v106.04,20.15 106.04,24.6 106.67,25.23 IC3.13
  Bottom 0.254: v106.04,20.15 116.2,20.15 116.83,19.52 118.1,19.52 118.74,18.88 118.74,18.25 119.38,18.25 SV1.9
N$18  (via drill 0.61)
  Top 0.254: v108.58,47.46 108.58,37.3 109.21,36.66 109.21,34.76 108.58,34.12 108.58,29.68 105.41,26.5 IC3.14 | v123.82,47.46 123.82,41.11 122.55,39.84 122.55,21.42 v123.19,20.79
  Bottom 0.254: v108.58,47.46 v123.82,47.46 | v123.19,20.79 120.64,20.79 SV1.11
N$19
  Top 0.254: IC3.17 97.15,24.6 98.42,23.33 98.42,16.98 100.96,14.44 100.96,4.28 103.5,1.74 120.01,1.74 120.01,6.18 121.28,7.46 121.28,21.42 120.01,22.7 SV1.13
N$20
  Bottom 0.254: IC3.18 95.24,25.23 96.52,23.96 105.41,23.96 106.04,24.6 106.04,27.77 117.47,27.77 119.38,25.87 SV1.15
N$21
  Top 0.254: IC18.1 197.48,20.79 196.84,20.79 R1.1 196.21,20.15 194.94,18.88 194.94,17.61 191.13,13.81 C3.1
N$22
  Top 0.254: R2.1 196.84,18.25 197.48,18.25 IC18.2
  Bottom 0.254: JP1.2 196.21,4.28 196.21,6.82 209.54,6.82 212.72,10 212.72,16.98 203.83,16.98 202.56,18.25 200.02,18.25 IC18.2
N$23  (via drill 0.61)
  Top 0.254: IC21.4 185.41,83.66 184.14,83.66 IC21.3 | v163.82,27.14 v163.82,13.17 | v191.76,27.14 191.76,30.95 191.13,31.58 191.13,44.28 v191.76,44.92
  Bottom 0.254: v163.82,13.17 167,13.17 IC27.5 | v163.82,27.14 168.27,27.14 168.91,26.5 179.06,26.5 179.7,27.14 v191.76,27.14 | v191.76,44.92 207.64,44.92 214.62,51.91 214.62,85.56 207.64,85.56 206.37,86.83 196.21,86.83 195.57,86.19 186.69,86.19 186.05,85.56 IC21.4
N$24  (via drill 0.61)
  Top 0.254: v44.45,47.46 44.45,56.35 45.08,56.98 45.08,61.43 46.35,62.7 v46.35,81.11 | v71.75,79.84 71.75,83.02 IC24.10
  Bottom 0.254: v44.45,47.46 45.08,46.82 50.8,46.82 51.43,47.46 IC26.2 | v46.35,81.11 50.8,81.11 52.7,79.21 71.11,79.21 v71.75,79.84
N$25  (via drill 0.61)
  Top 0.254: v75.56,36.03 75.56,47.46 74.29,48.73 74.29,58.89 75.56,60.16 75.56,81.11 74.29,82.39 74.29,83.02 IC24.11 | v55.24,36.66 55.24,45.55 53.97,46.82 53.97,47.46 IC26.3
  Bottom 0.254: v75.56,36.03 74.92,36.66 v55.24,36.66
N$26  (via drill 0.61)
  Top 0.254: v5.71,84.29 5.08,83.66 5.08,70.32 v5.71,69.69 | v4.44,68.41 3.8,67.78 3.8,59.52 v4.44,58.89 | v8.25,54.45 8.25,58.25 SV6.2 | v8.25,81.75 8.25,83.66 SV7.2
  Bottom 0.254: v5.71,84.29 7.62,84.29 SV7.2 | v4.44,68.41 v5.71,69.69 | v4.44,58.89 7.62,58.89 SV6.2 | v8.25,54.45 17.77,54.45 18.41,55.08 IC11.2 | v8.25,81.75 13.33,81.75 15.24,83.66 17.77,83.66 18.41,83.02 IC13.2
N$27
  Top 0.254: IC27.6 167.63,11.27 165.73,13.17 165.73,16.98 R11.A 166.37,18.88 167.63,20.15 IC27.2
  Bottom 0.254: C6.1 177.79,5.55 176.53,4.28 171.44,4.28 168.91,6.82 167,6.82 166.37,7.46 166.37,10.63 167,10.63 IC27.6
N$28
  Top 0.254: IC27.1 168.91,22.7 170.17,21.42 170.17,6.82 168.91,5.55 R9.1
  Bottom 0.254: R9.1 168.91,5.55 171.44,3.01 175.25,3.01 R10.2
N$29  (via drill 0.61)
  Top 0.254: v114.93,43.65 114.3,43.02 114.3,39.84 115.56,38.57 115.56,31.58 116.2,30.95 116.2,30.31 115.56,29.68 115.56,22.7 v116.2,22.06 | v103.5,20.15 103.5,34.12 102.23,35.39 103.5,36.66 v103.5,46.19
  Bottom 0.254: v114.93,43.65 116.83,43.65 SV2.10 | v116.2,22.06 115.56,22.7 109.21,22.7 107.94,21.42 105.41,21.42 104.77,20.79 104.13,20.79 v103.5,20.15 | v103.5,46.19 100.32,46.19 99.69,45.55 96.52,45.55 95.88,44.92 94.61,44.92 IC9.3
N$30
  Bottom 0.254: IC9.4 97.78,43.02 99.05,41.74 102.86,41.74 103.5,42.38 103.5,44.92 105.41,46.82 107.94,46.82 108.58,46.19 116.83,46.19 SV2.12
N$31  (via drill 0.61)
  Top 0.254: v104.77,47.46 104.77,44.92 IC9.7
  Bottom 0.254: v104.77,47.46 107.31,47.46 108.58,48.73 116.83,48.73 SV2.14
N$32  (via drill 0.61)
  Top 0.254: v107.31,48.73 107.31,44.92 IC9.8
  Bottom 0.254: v107.31,48.73 107.94,49.37 114.3,49.37 116.2,51.27 116.83,51.27 SV2.16
N$33  (via drill 0.61)
  Top 0.254: v12.7,43.65 12.06,43.02 12.06,41.11 10.16,41.11 9.52,40.48 9.52,32.85 10.16,32.22 SV4.1
  Bottom 0.254: v12.7,43.65 14.6,45.55 21.58,45.55 22.22,44.92 22.22,41.74 24.12,41.74 24.76,41.11 28.57,41.11 29.84,39.84 30.47,40.48 35.55,40.48 36.19,39.84 IC8.12
N$34
  Bottom 0.254: IC8.15 27.93,37.94 25.39,35.39 10.79,35.39 SV4.3
N$35  (via drill 0.61)
  Top 0.254: v13.33,37.94 13.97,37.3 13.97,32.85 12.06,30.95 13.33,29.68 v13.33,23.33 | v24.76,23.33 24.76,27.14 27.3,29.68 27.3,32.22 28.57,33.49 28.57,34.12 26.03,36.66 26.03,37.3 IC8.16
  Bottom 0.254: v13.33,37.94 12.7,37.3 11.43,37.3 SV4.5 | v13.33,23.33 v24.76,23.33
N$36
  Bottom 0.254: IC8.19 17.77,39.2 16.5,40.48 10.79,40.48 SV4.7
N$37  (via drill 0.61)
  Top 0.254: v121.91,88.1 121.91,57.62 118.74,54.45 118.74,35.39 118.1,34.76 118.1,33.49 SV2.2 | v83.18,88.1 83.18,79.84 83.81,79.21 83.81,60.16 83.18,59.52 83.18,36.66 83.81,36.03 v83.81,32.22
  Bottom 0.254: v121.91,88.1 119.38,88.1 118.74,88.73 118.1,88.1 113.66,88.1 113.02,87.47 89.53,87.47 88.89,88.1 86.35,88.1 85.72,88.73 84.45,88.73 83.81,88.1 v83.18,88.1 | v83.81,32.22 84.45,32.85 93.97,32.85 94.61,32.22 IC4.3
N$38  (via drill 0.61)
  Top 0.254: v97.15,36.03 97.15,32.22 IC4.4
  Bottom 0.254: v97.15,36.03 102.86,36.03 103.5,36.66 113.02,36.66 113.66,37.3 114.3,37.3 114.93,36.66 117.47,36.66 SV2.4
N$39  (via drill 0.61)
  Top 0.254: v104.77,35.39 104.77,32.22 IC4.7 | v114.3,36.03 v114.3,38.57
  Bottom 0.254: v104.77,35.39 105.41,36.03 v114.3,36.03 | v114.3,38.57 116.83,38.57 SV2.6
N$40  (via drill 0.61)
  Top 0.254: v106.04,40.48 106.04,32.22 106.67,31.58 IC4.8
  Bottom 0.254: v106.04,40.48 106.67,41.11 116.83,41.11 SV2.8
N$41  (via drill 0.61)
  Top 0.254: v106.04,45.55 106.04,50 106.67,50.63 IC9.13
  Bottom 0.254: v106.04,45.55 116.2,45.55 116.83,44.92 118.1,44.92 118.74,44.28 118.74,43.65 119.38,43.65 SV2.9
N$42  (via drill 0.61)
  Top 0.254: v130.17,46.19 129.53,46.82 129.53,78.58 v128.9,79.21 | v99.05,79.21 98.42,78.58 v98.42,49.37
  Bottom 0.254: v130.17,46.19 120.64,46.19 SV2.11 | v128.9,79.21 117.47,79.21 116.83,79.84 115.56,78.58 100.96,78.58 100.32,79.21 v99.05,79.21 | v98.42,49.37 104.13,49.37 104.77,50 IC9.14
N$43  (via drill 0.61)
  Top 0.254: v97.15,48.09 97.15,50 IC9.17 | v73.66,48.09 73.66,63.97 73.02,64.61 v73.02,90
  Bottom 0.254: v73.66,48.09 v97.15,48.09 | v73.02,90 83.18,90 83.81,89.37 86.35,89.37 86.99,88.73 89.53,88.73 90.16,88.1 112.39,88.1 113.02,88.73 117.47,88.73 118.1,89.37 121.91,89.37 122.55,90 139.69,90 141.6,88.1 141.6,68.41 137.16,68.41 121.91,53.17 121.91,48.73 120.64,48.73 SV2.13
N$44
  Bottom 0.254: IC9.18 95.24,51.91 96.52,53.17 117.47,53.17 119.38,51.27 SV2.15
N$45  (via drill 0.61)
  Top 0.254: v107.94,34.76 107.94,37.94 IC4.13
  Bottom 0.254: v107.94,34.76 118.1,34.76 118.74,34.12 120.01,34.12 SV2.1
N$46  (via drill 0.61)
  Top 0.254: v103.5,35.39 104.13,36.03 104.13,37.94 IC4.14 | v118.74,32.22 118.74,34.12 119.38,34.76 120.01,34.76 120.01,35.39 SV2.3
  Bottom 0.254: v103.5,35.39 106.04,32.85 116.2,32.85 116.83,32.22 v118.74,32.22
N$47
  Bottom 0.254: IC4.17 97.78,37.94 99.05,36.66 100.32,36.66 100.96,37.3 100.96,41.11 105.41,41.11 106.04,41.74 116.2,41.74 116.83,42.38 118.1,42.38 118.74,41.74 118.74,39.2 120.01,39.2 SV2.5
N$48  (via drill 0.61)
  Top 0.254: v122.55,41.11 121.91,40.48 121.91,6.82 121.28,6.18 v121.28,4.92 | v86.99,3.01 86.99,16.34 86.35,16.98 86.35,25.23 87.62,26.5 v87.62,36.03
  Bottom 0.254: v122.55,41.11 120.64,41.11 SV2.7 | v121.28,4.92 118.74,2.38 102.23,2.38 100.96,3.64 99.69,3.64 98.42,2.38 87.62,2.38 v86.99,3.01 | v87.62,36.03 88.26,36.66 93.97,36.66 94.61,37.3 IC4.18
N$49  (via drill 0.61)
  Top 0.254: v26.03,34.12 26.03,32.22 IC8.5
  Bottom 0.254: v26.03,34.12 25.39,34.76 15.24,34.76 14.6,34.12 12.06,34.12 11.43,33.49 8.89,33.49 8.25,34.12 SV4.4
N$50  (via drill 0.61)
  Top 0.254: v12.7,32.85 12.06,33.49 v12.06,38.57
  Bottom 0.254: v12.7,32.85 13.33,33.49 25.39,33.49 26.03,32.85 27.93,32.85 28.57,32.22 IC8.6 | v12.06,38.57 9.52,38.57 8.89,37.94 8.25,37.94 SV4.6
N$51  (via drill 0.61)
  Top 0.254: v8.25,29.04 8.25,31.58 SV4.2
  Bottom 0.254: v8.25,29.04 17.77,29.04 18.41,29.68 IC8.2
N$52
  Bottom 0.254: IC8.9 35.55,30.31 34.29,29.04 22.86,29.04 22.22,29.68 22.22,32.85 13.97,32.85 12.06,30.95 7.62,30.95 6.98,31.58 6.98,39.84 7.62,39.84 SV4.8
N$53  (via drill 0.61)
  Top 0.254: v36.19,8.73 36.19,11.9 IC6.12
  Bottom 0.254: v36.19,8.73 35.55,8.09 31.11,8.09 30.47,7.46 19.04,7.46 17.77,8.73 17.14,8.73 16.5,8.09 11.43,8.09 SV3.1
N$54  (via drill 0.61)
  Top 0.254: v23.49,10.63 24.76,11.9 25.39,11.27 26.66,11.27 27.93,12.54 IC6.15 | v12.7,10.63 v12.7,15.08
  Bottom 0.254: v23.49,10.63 22.22,11.9 22.22,14.44 21.58,15.08 20.31,15.08 19.68,14.44 19.68,11.9 19.04,11.27 17.77,11.27 17.14,11.9 17.14,14.44 16.5,15.08 v12.7,15.08 | v12.7,10.63 11.43,10.63 SV3.3
N$55  (via drill 0.61)
  Top 0.254: v18.41,15.71 17.14,14.44 v17.14,7.46 | v5.08,7.46 5.71,8.09 5.71,15.08 5.08,15.71 6.34,16.98 8.89,16.98 9.52,16.34 9.52,13.17 10.16,13.17 SV3.5
  Bottom 0.254: v18.41,15.71 22.22,15.71 22.86,15.08 25.39,15.08 26.03,14.44 IC6.16 | v17.14,7.46 12.06,7.46 11.43,6.82 7.62,6.82 6.98,7.46 v5.08,7.46
N$56
  Bottom 0.254: IC6.19 18.41,14.44 17.14,15.71 13.33,15.71 12.7,16.34 10.79,16.34 SV3.7
N$57  (via drill 0.61)
  Top 0.254: v8.25,3.64 8.25,7.46 SV3.2
  Bottom 0.254: v8.25,3.64 17.77,3.64 18.41,4.28 IC6.2
N$58  (via drill 0.61)
  Top 0.254: v26.03,8.73 26.03,6.82 IC6.5
  Bottom 0.254: v26.03,8.73 22.22,8.73 20.95,10 13.97,10 13.33,9.36 8.89,9.36 8.25,10 SV3.4
N$59  (via drill 0.61)
  Top 0.254: v28.57,2.38 28.57,4.28 IC6.6 | v9.52,2.38 9.52,11.27 8.89,11.9 8.89,13.17 SV3.6
  Bottom 0.254: v28.57,2.38 27.93,1.74 10.16,1.74 v9.52,2.38
N$60  (via drill 0.61)
  Top 0.254: v6.34,15.71 6.34,6.18 6.98,5.55 v6.98,4.92 | v13.97,4.92 15.87,3.01 19.68,3.01 v19.68,3.64
  Bottom 0.254: v6.34,15.71 7.62,15.71 SV3.8 | v6.98,4.92 v13.97,4.92 | v19.68,3.64 35.55,3.64 36.19,4.28 IC6.9
N$61
  Bottom 0.254: IC7.19 17.77,26.5 16.5,27.77 13.33,27.77 11.43,25.87 SV3.15
N$62
  Bottom 0.254: IC7.16 25.39,25.23 24.12,23.96 13.97,23.96 13.33,24.6 12.7,24.6 11.43,23.33 SV3.13
N$63
  Top 0.254: IC7.15 28.57,24.6 28.57,21.42 29.84,20.15 29.84,10.63 27.3,8.09 27.3,4.28 24.76,1.74 12.7,1.74 12.7,9.36 13.97,10.63 13.97,16.98 10.79,20.15 SV3.11
N$64
  Bottom 0.254: IC7.12 35.55,26.5 34.29,27.77 17.77,27.77 17.14,28.41 8.89,28.41 6.98,26.5 6.98,19.52 8.89,19.52 10.16,18.25 SV3.9
N$65
  Bottom 0.254: IC7.2 17.77,17.61 16.5,16.34 13.97,16.34 13.33,16.98 10.16,16.98 8.89,18.25 SV3.10
N$66
  Bottom 0.254: IC7.5 25.39,18.88 24.12,20.15 17.77,20.15 17.14,19.52 16.5,20.15 12.06,20.15 11.43,19.52 10.16,19.52 8.89,20.79 SV3.12
N$67  (via drill 0.61)
  Top 0.254: v27.3,22.06 27.93,21.42 27.93,20.79 28.57,20.15 28.57,19.52 IC7.6
  Bottom 0.254: v27.3,22.06 8.89,22.06 8.25,22.7 SV3.14
N$68  (via drill 0.61)
  Top 0.254: v6.98,56.98 6.98,50 6.34,49.37 6.34,27.14 7.62,25.87 SV3.16 | v13.97,56.98 17.14,60.16 v17.14,71.59 | v29.2,72.86 29.84,72.22 29.84,42.38 32.38,39.84 32.38,37.3 33.02,36.66 33.02,32.85 32.38,32.22 32.38,11.9 33.02,11.27 34.92,11.27 34.92,15.71 35.55,16.34 35.55,17.61 IC7.9
  Bottom 0.254: v6.98,56.98 v13.97,56.98 | v17.14,71.59 20.95,71.59 22.22,72.86 22.86,72.86 23.49,73.5 24.76,72.22 28.57,72.22 v29.2,72.86
N$69
  Bottom 0.254: IC10.2 17.77,43.02 15.87,41.11 10.16,41.11 8.89,42.38 SV4.10
N$70
  Bottom 0.254: IC10.5 26.03,44.92 26.03,46.19 25.39,46.82 12.06,46.82 11.43,46.19 10.16,46.19 8.89,44.92 SV4.12
N$71
  Bottom 0.254: IC10.6 27.93,43.02 26.66,41.74 25.39,41.74 24.76,42.38 24.76,46.19 13.97,46.19 11.43,43.65 7.62,43.65 6.98,44.28 6.98,47.46 7.62,47.46 SV4.14
N$72
  Bottom 0.254: IC10.9 36.19,44.92 34.92,46.19 32.38,46.19 30.47,48.09 26.66,48.09 26.03,48.73 19.68,48.73 19.04,48.09 12.06,48.09 11.43,48.73 10.16,48.73 8.89,50 SV4.16
N$73
  Top 0.254: IC10.19 17.77,51.91 16.5,53.17 10.79,53.17 10.79,50.63 SV4.15
N$74  (via drill 0.61)
  Top 0.254: v26.03,47.46 26.03,50 IC10.16
  Bottom 0.254: v26.03,47.46 11.43,47.46 SV4.13
N$75  (via drill 0.61)
  Top 0.254: v12.7,50 12.7,49.37 12.06,48.73 12.06,45.55 11.43,44.92 SV4.11
  Bottom 0.254: v12.7,50 13.33,50 14.6,48.73 18.41,48.73 19.68,50 19.68,53.17 27.93,53.17 28.57,52.54 IC10.15
N$76  (via drill 0.61)
  Top 0.254: v36.19,46.19 36.19,50 IC10.12 | v44.45,46.19 44.45,39.84 43.18,38.57 43.18,36.66 43.81,36.03 43.81,27.77 v43.18,27.14 | v19.68,29.04 14.6,29.04 14.6,39.84 13.97,40.48 13.97,43.65 12.7,44.92 11.43,43.65 11.43,42.38 SV4.9
  Bottom 0.254: v44.45,46.19 v36.19,46.19 | v43.18,27.14 40,27.14 38.1,29.04 36.83,29.04 36.19,28.41 20.31,28.41 v19.68,29.04
N$77
  Bottom 0.254: IC16.3 95.24,68.41 96.52,67.14 114.93,67.14 116.83,69.05 SV5.10
N$78  (via drill 0.61)
  Top 0.254: v100.96,70.95 v100.96,79.84 | v115.56,79.84 115.56,72.86 116.83,71.59 SV5.12
  Bottom 0.254: v100.96,70.95 97.78,70.95 97.15,70.32 IC16.4 | v100.96,79.84 101.59,79.21 114.93,79.21 v115.56,79.84
N$79  (via drill 0.61)
  Top 0.254: v104.77,73.5 104.77,70.32 IC16.7
  Bottom 0.254: v104.77,73.5 108.58,73.5 109.21,74.13 116.83,74.13 SV5.14
N$80  (via drill 0.61)
  Top 0.254: v108.58,74.77 108.58,70.32 107.94,69.69 IC16.8
  Bottom 0.254: v108.58,74.77 113.02,74.77 114.93,76.67 116.83,76.67 SV5.16
N$81  (via drill 0.61)
  Top 0.254: v13.33,66.51 13.97,65.88 13.97,62.7 14.6,62.06 14.6,58.89 12.7,56.98 11.43,58.25 11.43,58.89 SV6.1
  Bottom 0.254: v13.33,66.51 34.29,66.51 34.92,65.88 35.55,65.88 36.19,65.24 IC11.12
N$82
  Bottom 0.254: IC11.15 27.93,63.34 26.03,61.43 11.43,61.43 SV6.3
N$83
  Bottom 0.254: IC11.16 25.39,63.34 24.12,62.06 13.33,62.06 11.43,63.97 SV6.5
N$84
  Bottom 0.254: IC11.19 17.77,64.61 16.5,65.88 13.97,65.88 13.33,65.24 12.7,65.24 11.43,66.51 SV6.7
N$85  (via drill 0.61)
  Top 0.254: v43.81,88.1 44.45,87.47 v44.45,76.03
  Bottom 0.254: v43.81,88.1 43.18,87.47 36.83,87.47 36.19,88.1 IC13.12 | v44.45,76.03 43.81,75.4 41.27,75.4 40.64,74.77 33.02,74.77 32.38,75.4 32.38,78.58 25.39,78.58 24.12,79.84 22.86,79.84 22.22,80.48 22.22,83.02 21.58,83.66 20.95,83.66 19.68,84.92 19.04,84.92 18.41,84.29 13.33,84.29 12.7,83.66 12.06,84.29 11.43,84.29 SV7.1
N$86  (via drill 0.61)
  Top 0.254: v13.97,88.1 13.97,83.66 v13.33,83.02 | v9.52,83.02 9.52,84.92 10.16,85.56 10.16,86.83 SV7.3
  Bottom 0.254: v13.97,88.1 14.6,87.47 24.76,87.47 24.76,90.64 25.39,91.28 26.66,91.28 27.3,90.64 28.57,90.64 IC13.15 | v9.52,83.02 v13.33,83.02
N$87  (via drill 0.61)
  Top 0.254: v12.7,88.1 13.33,87.47 13.33,85.56 v12.7,84.92
  Bottom 0.254: v12.7,88.1 12.06,88.73 10.79,88.73 SV7.5 | v12.7,84.92 17.77,84.92 18.41,85.56 24.76,85.56 26.03,84.29 26.66,84.92 28.57,84.92 29.84,86.19 29.84,86.83 29.2,86.83 28.57,87.47 26.03,87.47 26.03,88.1 IC13.16
N$88
  Bottom 0.254: IC13.19 17.77,90 15.87,91.91 11.43,91.91 SV7.7
N$89
  Bottom 0.254: IC11.5 25.39,56.98 24.12,58.25 12.06,58.25 11.43,57.62 10.16,57.62 9.52,58.25 9.52,59.52 8.25,60.8 SV6.4
N$90
  Bottom 0.254: IC11.6 27.93,56.98 24.76,60.16 10.16,60.16 9.52,60.8 9.52,63.34 8.25,63.34 SV6.6
N$91  (via drill 0.61)
  Top 0.254: v43.81,58.25 44.45,58.89 44.45,62.06 45.72,63.34 45.72,80.48 45.08,81.11 v45.08,98.26 | v29.84,98.26 29.84,103.34 27.3,105.88 9.52,105.88 9.52,98.89 8.89,98.26 7.62,98.26 4.44,95.08 4.44,69.69 7.62,66.51 SV6.8
  Bottom 0.254: v43.81,58.25 36.83,58.25 36.19,57.62 IC11.9 | v29.84,98.26 v45.08,98.26
N$92  (via drill 0.61)
  Top 0.254: v27.3,79.84 27.3,104.61 26.66,105.25 15.24,105.25 15.24,103.97 13.97,102.7 13.97,101.44 v13.33,100.8 | v5.08,100.8 5.08,96.99 3.8,95.72 3.8,82.39 v3.17,81.75
  Bottom 0.254: v27.3,79.84 27.93,79.21 34.92,79.21 36.19,77.94 IC12.12 | v5.08,100.8 v13.33,100.8 | v3.17,81.75 2.54,81.75 1.27,80.48 1.27,76.67 7.62,70.32 8.89,70.32 9.52,69.69 9.52,69.05 10.16,69.05 SV6.9
N$93
  Bottom 0.254: IC12.15 28.57,75.4 28.57,73.5 24.76,73.5 24.12,74.13 22.22,74.13 20.95,72.86 12.7,72.86 11.43,71.59 SV6.11
N$94  (via drill 0.61)
  Top 0.254: v76.83,57.62 76.83,83.02 IC24.12
  Bottom 0.254: v76.83,57.62 69.84,50.63 57.15,50.63 56.51,50 IC26.4
N$95
  Bottom 0.254: IC12.16 25.39,77.3 24.12,78.58 20.31,78.58 19.68,77.94 19.68,74.13 11.43,74.13 SV6.13
N$96
  Bottom 0.254: IC12.19 17.77,76.03 16.5,74.77 13.97,74.77 12.06,76.67 11.43,76.67 SV6.15
N$97  (via drill 0.61)
  Top 0.254: v6.34,77.94 6.34,70.32 7.62,69.05 SV6.10 | v14.6,78.58 17.14,78.58 17.14,74.13 18.41,72.86 18.41,70.32 IC12.2
  Bottom 0.254: v6.34,77.94 13.33,77.94 13.97,78.58 v14.6,78.58
N$98  (via drill 0.61)
  Top 0.254: v27.3,74.77 26.03,73.5 26.03,70.32 IC12.5
  Bottom 0.254: v27.3,74.77 21.58,74.77 20.31,73.5 12.06,73.5 11.43,72.86 9.52,72.86 8.89,72.22 8.25,72.22 SV6.12
N$99  (via drill 0.61)
  Top 0.254: v9.52,67.78 9.52,72.22 8.89,72.86 8.89,74.13 SV6.14
  Bottom 0.254: v9.52,67.78 14.6,67.78 15.24,67.14 26.66,67.14 27.3,67.78 28.57,67.78 IC12.6
N$100  (via drill 0.61)
  Top 0.254: v12.06,75.4 12.7,74.77 12.7,70.95 v12.06,70.32
  Bottom 0.254: v12.06,75.4 8.89,75.4 8.25,76.03 SV6.16 | v12.06,70.32 14.6,70.32 15.24,70.95 16.5,70.95 17.14,70.32 17.77,70.95 34.29,70.95 34.92,70.32 36.19,70.32 IC12.9
N$101  (via drill 0.61)
  Top 0.254: v93.34,65.88 93.34,60.8 93.97,60.16 93.97,56.98 IC15.3 | v103.5,72.22 v103.5,80.48 | v120.64,80.48 121.28,79.84 121.28,58.25 119.38,56.35 117.47,56.35 117.47,58.25 SV5.2
  Bottom 0.254: v93.34,65.88 93.34,70.95 96.52,70.95 97.15,71.59 100.32,71.59 100.96,72.22 v103.5,72.22 | v103.5,80.48 104.13,79.84 114.3,79.84 115.56,81.11 120.01,81.11 v120.64,80.48
N$102  (via drill 0.61)
  Top 0.254: v85.72,58.25 v85.72,87.47 | v118.74,87.47 118.74,62.7 118.1,62.06 118.1,61.43 SV5.4
  Bottom 0.254: v85.72,58.25 96.52,58.25 97.15,57.62 IC15.4 | v85.72,87.47 88.26,87.47 88.89,86.83 113.66,86.83 114.3,87.47 v118.74,87.47
N$103  (via drill 0.61)
  Top 0.254: v104.77,60.8 104.77,57.62 IC15.7 | v114.3,61.43 v114.3,63.97
  Bottom 0.254: v104.77,60.8 105.41,61.43 v114.3,61.43 | v114.3,63.97 116.83,63.97 SV5.6
N$104  (via drill 0.61)
  Top 0.254: v106.04,65.88 106.04,57.62 106.67,56.98 IC15.8
  Bottom 0.254: v106.04,65.88 106.67,66.51 116.83,66.51 SV5.8
N$105  (via drill 0.61)
  Top 0.254: v107.31,71.59 107.31,75.4 IC16.13
  Bottom 0.254: v107.31,71.59 107.94,70.95 116.2,70.95 116.83,70.32 118.1,70.32 118.74,69.69 118.74,69.05 119.38,69.05 SV5.9
N$106  (via drill 0.61)
  Top 0.254: v106.04,72.22 106.04,75.4 105.41,76.03 IC16.14
  Bottom 0.254: v106.04,72.22 106.67,72.86 118.1,72.86 118.74,72.22 120.01,72.22 SV5.11
N$107  (via drill 0.61)
  Top 0.254: v99.05,84.92 98.42,84.29 98.42,81.75 97.78,81.11 97.78,77.3 IC16.17 | v123.82,84.92 123.19,84.29 123.19,74.77 v123.82,74.13
  Bottom 0.254: v99.05,84.92 99.69,85.56 113.66,85.56 114.3,84.92 v123.82,84.92 | v123.82,74.13 120.64,74.13 SV5.13
N$108  (via drill 0.61)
